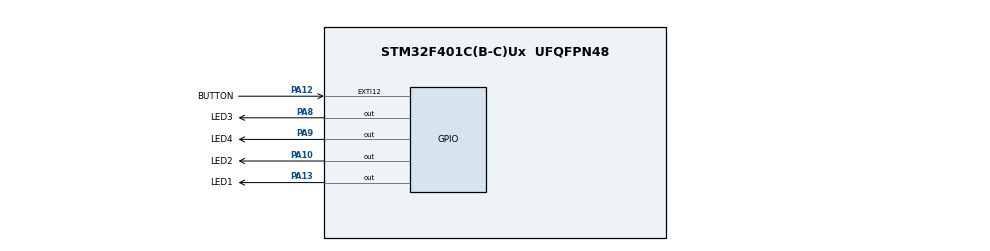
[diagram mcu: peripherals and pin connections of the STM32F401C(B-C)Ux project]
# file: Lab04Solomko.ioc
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Mcu.Family=STM32F4
Mcu.Name=STM32F401C(B-C)Ux
Mcu.Package=UFQFPN48
NVIC.EXTI15_10_IRQn=true\:0\:0\:false\:true\:true\:2\:true\:true\:true
NVIC.PriorityGroup=NVIC_PRIORITYGROUP_4
NVIC.TIM2_IRQn=true\:0\:0\:false\:true\:true\:1\:true\:true\:true
NVIC.TIM3_IRQn=true\:0\:0\:false\:true\:true\:3\:true\:true\:true
NVIC.TIM4_IRQn=true\:0\:0\:false\:true\:true\:4\:true\:true\:true
PA10.GPIO_Label=LED2
PA10.Signal=GPIO_Output
PA12.GPIO_Label=BUTTON
PA12.Signal=GPXTI12
PA13.GPIO_Label=LED1
PA13.Signal=GPIO_Output
PA8.GPIO_Label=LED3
PA8.Signal=GPIO_Output
PA9.GPIO_Label=LED4
PA9.Signal=GPIO_Output
ProjectManager.HeapSize=0x200
ProjectManager.StackSize=0x400
ProjectManager.TargetToolchain=STM32CubeIDE
RCC.AHBCLKDivider=RCC_SYSCLK_DIV2
RCC.AHBFreq_Value=8000000
RCC.APB1Freq_Value=8000000
RCC.APB1TimFreq_Value=8000000
RCC.APB2Freq_Value=8000000
RCC.APB2TimFreq_Value=8000000
RCC.CortexFreq_Value=8000000
RCC.HCLKFreq_Value=8000000
RCC.HSE_VALUE=25000000
RCC.HSI_VALUE=16000000
RCC.LSE_VALUE=32768
RCC.SYSCLKFreq_VALUE=16000000
RCC.VCOOutputFreq_Value=192000000
TIM2.Period=200
TIM2.Prescaler=8000
TIM2.TIM_MasterOutputTrigger=TIM_TRGO_UPDATE
TIM3.Period=400
TIM3.Prescaler=4000
TIM3.TIM_MasterOutputTrigger=TIM_TRGO_UPDATE
TIM4.Period=800
TIM4.Prescaler=2000
TIM4.TIM_MasterOutputTrigger=TIM_TRGO_UPDATE
VP_TIM2_VS_ClockSourceINT.Mode=Internal
VP_TIM3_VS_ClockSourceINT.Mode=Internal
VP_TIM4_VS_ClockSourceINT.Mode=Internal
board=custom

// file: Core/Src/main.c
/* USER CODE BEGIN Header */
/**
  ******************************************************************************
  * @file           : main.c
  * @brief          : Main program body
  ******************************************************************************
  * @attention
  *
  * Copyright (c) 2022 STMicroelectronics.
  * All rights reserved.
  *
  * This software is licensed under terms that can be found in the LICENSE file
  * in the root directory of this software component.
  * If no LICENSE file comes with this software, it is provided AS-IS.
  *
  ******************************************************************************
  */
/* USER CODE END Header */
#include "main.h"
#include <stdbool.h>

TIM_HandleTypeDef htim2;
TIM_HandleTypeDef htim3;
TIM_HandleTypeDef htim4;

void SystemClock_Config(void);
static void MX_GPIO_Init(void);
static void MX_TIM2_Init(void);
static void MX_TIM3_Init(void);
static void MX_TIM4_Init(void);
static void MX_NVIC_Init(void);

/* USER CODE BEGIN 0 */
bool flag = false;
int GPIO_PIN[] = { LED1_Pin, LED2_Pin, LED3_Pin, LED4_Pin };
/* USER CODE END 0 */

int main(void)
{

  /* MCU Configuration--------------------------------------------------------*/

  /* Reset of all peripherals, Initializes the Flash interface and the Systick. */
  HAL_Init();

  /* Configure the system clock */
  SystemClock_Config();

  /* Initialize all configured peripherals */
  MX_GPIO_Init();
  MX_TIM2_Init();
  MX_TIM3_Init();
  MX_TIM4_Init();

  /* Initialize interrupts */
  MX_NVIC_Init();
  /* USER CODE BEGIN 2 */
HAL_TIM_Base_Start_IT(&htim2);
HAL_TIM_Base_Start_IT(&htim3);
HAL_TIM_Base_Start_IT(&htim4);

  /* USER CODE END 2 */

  /* Infinite loop */
  while (1)
  {
	  HAL_GPIO_TogglePin(LED2_GPIO_Port, LED2_Pin);
	  	 	 	  HAL_Delay(500);
  }
}

void SystemClock_Config(void)
{
  RCC_OscInitTypeDef RCC_OscInitStruct = {0};
  RCC_ClkInitTypeDef RCC_ClkInitStruct = {0};

  /** Configure the main internal regulator output voltage
  */
  __HAL_RCC_PWR_CLK_ENABLE();
  __HAL_PWR_VOLTAGESCALING_CONFIG(PWR_REGULATOR_VOLTAGE_SCALE2);

  /** Initializes the RCC Oscillators according to the specified parameters
  * in the RCC_OscInitTypeDef structure.
  */
  RCC_OscInitStruct.OscillatorType = RCC_OSCILLATORTYPE_HSI;
  RCC_OscInitStruct.HSIState = RCC_HSI_ON;
  RCC_OscInitStruct.HSICalibrationValue = RCC_HSICALIBRATION_DEFAULT;
  RCC_OscInitStruct.PLL.PLLState = RCC_PLL_NONE;
  if (HAL_RCC_OscConfig(&RCC_OscInitStruct) != HAL_OK)
  {
    Error_Handler();
  }

  /** Initializes the CPU, AHB and APB buses clocks
  */
  RCC_ClkInitStruct.ClockType = RCC_CLOCKTYPE_HCLK|RCC_CLOCKTYPE_SYSCLK
                              |RCC_CLOCKTYPE_PCLK1|RCC_CLOCKTYPE_PCLK2;
  RCC_ClkInitStruct.SYSCLKSource = RCC_SYSCLKSOURCE_HSI;
  RCC_ClkInitStruct.AHBCLKDivider = RCC_SYSCLK_DIV1;
  RCC_ClkInitStruct.APB1CLKDivider = RCC_HCLK_DIV1;
  RCC_ClkInitStruct.APB2CLKDivider = RCC_HCLK_DIV1;

  if (HAL_RCC_ClockConfig(&RCC_ClkInitStruct, FLASH_LATENCY_0) != HAL_OK)
  {
    Error_Handler();
  }
}

/**
  * @brief NVIC Configuration.
  * @retval None
  */
static void MX_NVIC_Init(void)
{
  /* TIM2_IRQn interrupt configuration */
  HAL_NVIC_SetPriority(TIM2_IRQn, 0, 0);
  HAL_NVIC_EnableIRQ(TIM2_IRQn);
  /* TIM3_IRQn interrupt configuration */
  HAL_NVIC_SetPriority(TIM3_IRQn, 0, 0);
  HAL_NVIC_EnableIRQ(TIM3_IRQn);
  /* TIM4_IRQn interrupt configuration */
  HAL_NVIC_SetPriority(TIM4_IRQn, 0, 0);
  HAL_NVIC_EnableIRQ(TIM4_IRQn);
  /* EXTI15_10_IRQn interrupt configuration */
  HAL_NVIC_SetPriority(EXTI15_10_IRQn, 0, 0);
  HAL_NVIC_EnableIRQ(EXTI15_10_IRQn);
}

static void MX_TIM2_Init(void)
{

  TIM_ClockConfigTypeDef sClockSourceConfig = {0};
  TIM_MasterConfigTypeDef sMasterConfig = {0};

  htim2.Instance = TIM2;
  htim2.Init.Prescaler = 8000;
  htim2.Init.CounterMode = TIM_COUNTERMODE_UP;
  htim2.Init.Period = 200;
  htim2.Init.ClockDivision = TIM_CLOCKDIVISION_DIV1;
  htim2.Init.AutoReloadPreload = TIM_AUTORELOAD_PRELOAD_DISABLE;
  if (HAL_TIM_Base_Init(&htim2) != HAL_OK)
  {
    Error_Handler();
  }
  sClockSourceConfig.ClockSource = TIM_CLOCKSOURCE_INTERNAL;
  if (HAL_TIM_ConfigClockSource(&htim2, &sClockSourceConfig) != HAL_OK)
  {
    Error_Handler();
  }
  sMasterConfig.MasterOutputTrigger = TIM_TRGO_UPDATE;
  sMasterConfig.MasterSlaveMode = TIM_MASTERSLAVEMODE_DISABLE;
  if (HAL_TIMEx_MasterConfigSynchronization(&htim2, &sMasterConfig) != HAL_OK)
  {
    Error_Handler();
  }

}

static void MX_TIM3_Init(void)
{

  TIM_ClockConfigTypeDef sClockSourceConfig = {0};
  TIM_MasterConfigTypeDef sMasterConfig = {0};

  htim3.Instance = TIM3;
  htim3.Init.Prescaler = 8000;
  htim3.Init.CounterMode = TIM_COUNTERMODE_UP;
  htim3.Init.Period = 300;
  htim3.Init.ClockDivision = TIM_CLOCKDIVISION_DIV1;
  htim3.Init.AutoReloadPreload = TIM_AUTORELOAD_PRELOAD_DISABLE;
  if (HAL_TIM_Base_Init(&htim3) != HAL_OK)
  {
    Error_Handler();
  }
  sClockSourceConfig.ClockSource = TIM_CLOCKSOURCE_INTERNAL;
  if (HAL_TIM_ConfigClockSource(&htim3, &sClockSourceConfig) != HAL_OK)
  {
    Error_Handler();
  }
  sMasterConfig.MasterOutputTrigger = TIM_TRGO_UPDATE;
  sMasterConfig.MasterSlaveMode = TIM_MASTERSLAVEMODE_DISABLE;
  if (HAL_TIMEx_MasterConfigSynchronization(&htim3, &sMasterConfig) != HAL_OK)
  {
    Error_Handler();
  }

}

static void MX_TIM4_Init(void)
{

  TIM_ClockConfigTypeDef sClockSourceConfig = {0};
  TIM_MasterConfigTypeDef sMasterConfig = {0};

  htim4.Instance = TIM4;
  htim4.Init.Prescaler = 8000;
  htim4.Init.CounterMode = TIM_COUNTERMODE_UP;
  htim4.Init.Period = 100;
  htim4.Init.ClockDivision = TIM_CLOCKDIVISION_DIV1;
  htim4.Init.AutoReloadPreload = TIM_AUTORELOAD_PRELOAD_DISABLE;
  if (HAL_TIM_Base_Init(&htim4) != HAL_OK)
  {
    Error_Handler();
  }
  sClockSourceConfig.ClockSource = TIM_CLOCKSOURCE_INTERNAL;
  if (HAL_TIM_ConfigClockSource(&htim4, &sClockSourceConfig) != HAL_OK)
  {
    Error_Handler();
  }
  sMasterConfig.MasterOutputTrigger = TIM_TRGO_UPDATE;
  sMasterConfig.MasterSlaveMode = TIM_MASTERSLAVEMODE_DISABLE;
  if (HAL_TIMEx_MasterConfigSynchronization(&htim4, &sMasterConfig) != HAL_OK)
  {
    Error_Handler();
  }

}

static void MX_GPIO_Init(void)
{
  GPIO_InitTypeDef GPIO_InitStruct = {0};

  /* GPIO Ports Clock Enable */
  __HAL_RCC_GPIOB_CLK_ENABLE();
  __HAL_RCC_GPIOA_CLK_ENABLE();

  /*Configure GPIO pin Output Level */
  HAL_GPIO_WritePin(GPIOA, LED1_Pin|LED3_Pin|LED4_Pin|LED2_Pin, GPIO_PIN_RESET);

  /*Configure GPIO pin : BUTTON_Pin */
  GPIO_InitStruct.Pin = BUTTON_Pin;
  GPIO_InitStruct.Mode = GPIO_MODE_IT_RISING_FALLING;
  GPIO_InitStruct.Pull = GPIO_NOPULL;
  HAL_GPIO_Init(BUTTON_GPIO_Port, &GPIO_InitStruct);

  /*Configure GPIO pins : LED1_Pin LED3_Pin LED4_Pin LED2_Pin */
  GPIO_InitStruct.Pin = LED1_Pin|LED3_Pin|LED4_Pin|LED2_Pin;
  GPIO_InitStruct.Mode = GPIO_MODE_OUTPUT_PP;
  GPIO_InitStruct.Pull = GPIO_NOPULL;
  GPIO_InitStruct.Speed = GPIO_SPEED_FREQ_LOW;
  HAL_GPIO_Init(GPIOA, &GPIO_InitStruct);

}

/* USER CODE BEGIN 4 */
void HAL_GPIO_EXTI_Callback(uint16_t GPIO_Pin)
{

	if(GPIO_Pin==BUTTON_Pin)
	{

		flag=!flag;
	}

}

void HAL_TIM_PeriodElapsedCallback(TIM_HandleTypeDef *htim)
{

	if(htim->Instance==TIM2)
		{

			if(!flag)
				HAL_GPIO_TogglePin(LED1_GPIO_Port, LED1_Pin);

		}
		if(htim->Instance==TIM3)
			{

			if(!flag)
					HAL_GPIO_TogglePin(LED3_GPIO_Port, LED3_Pin);

			}
		if(htim->Instance==TIM4)
			{

			if(!flag)
					HAL_GPIO_TogglePin(LED4_GPIO_Port, LED4_Pin);

			}

}

/* USER CODE END 4 */

void Error_Handler(void)
{
  __disable_irq();
  while (1)
  {
  }
}
